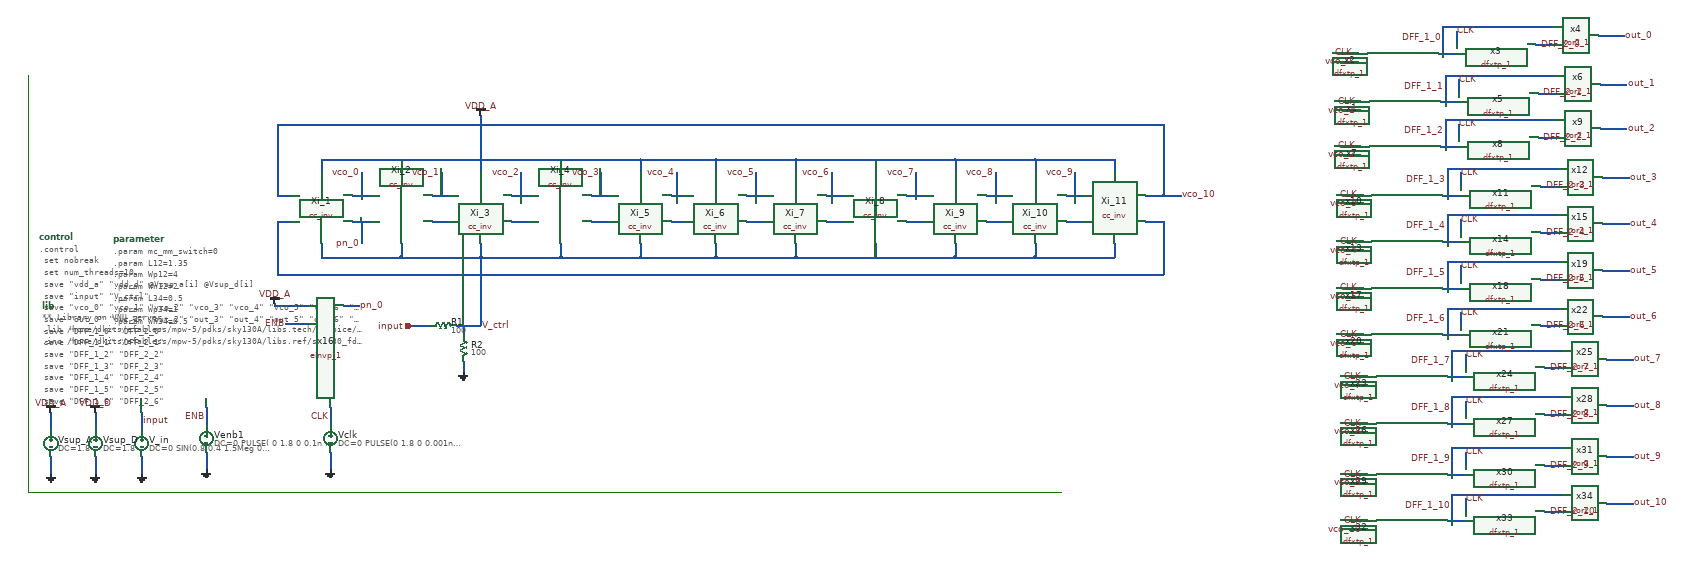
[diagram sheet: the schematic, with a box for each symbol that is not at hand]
v {xschem version=3.0.0 file_version=1.2 }
G {}
K {}
V {}
S {}
E {}
L 4 0 -540 -0 -0 {}
L 4 -0 0 520 -0 {}
L 4 520 -0 580 -0 {}
L 4 580 -0 800 0 {}
L 4 800 -0 885 0 {}
L 4 -0 -615 -0 -540 {}
L 4 885 -0 1180 -0 {}
L 4 1180 0 1210 0 {}
L 4 1210 -0 1310 -0 {}
L 4 -0 -860 0 -610 {}
L 4 0 -940 -0 -860 {}
L 4 1310 0 2330 -0 {}
N 50 -180 50 -140 { lab=VDD_A}
N 50 -80 50 -40 { lab=GND}
N 255 -80 255 -40 { lab=GND}
N 255 -180 255 -140 { lab=input}
N 400 -90 400 -50 { lab=GND}
N 400 -190 400 -150 { lab=ENB}
N 980 -375 980 -355 { lab=V_ctrl}
N 980 -295 980 -270 { lab=GND}
N 865 -375 905 -375 { lab=input}
N 150 -180 150 -140 { lab=VDD_D}
N 150 -80 150 -40 { lab=GND}
N 680 -90 680 -50 { lab=GND}
N 680 -190 680 -150 { lab=CLK}
N 3180 -990 3200 -990 { lab=DFF_1_0}
N 3400 -1010 3420 -1010 { lab=DFF_2_0}
N 3540 -1030 3600 -1030 { lab=out_0}
N 2960 -990 3000 -990 { lab=CLK}
N 2960 -970 3000 -970 { lab=vco_0}
N 3200 -1050 3420 -1050 { lab=DFF_1_0}
N 3200 -990 3220 -990 { lab=DFF_1_0}
N 3220 -1040 3220 -1010 { lab=CLK}
N 3190 -1050 3200 -1050 { lab=DFF_1_0}
N 3190 -1050 3190 -990 { lab=DFF_1_0}
N 3420 -1050 3440 -1050 { lab=DFF_1_0}
N 3420 -1010 3440 -1010 { lab=DFF_2_0}
N 3185 -880 3205 -880 { lab=DFF_1_1}
N 3405 -900 3425 -900 { lab=DFF_2_1}
N 3545 -920 3605 -920 { lab=out_1}
N 2965 -880 3005 -880 { lab=CLK}
N 2965 -860 3005 -860 { lab=vco_1}
N 3205 -940 3425 -940 { lab=DFF_1_1}
N 3205 -880 3225 -880 { lab=DFF_1_1}
N 3225 -930 3225 -900 { lab=CLK}
N 3195 -940 3205 -940 { lab=DFF_1_1}
N 3195 -940 3195 -880 { lab=DFF_1_1}
N 3425 -940 3445 -940 { lab=DFF_1_1}
N 3425 -900 3445 -900 { lab=DFF_2_1}
N 3185 -780 3205 -780 { lab=DFF_1_2}
N 3405 -800 3425 -800 { lab=DFF_2_2}
N 3545 -820 3605 -820 { lab=out_2}
N 2965 -780 3005 -780 { lab=CLK}
N 2965 -760 3005 -760 { lab=vco_2}
N 3205 -840 3425 -840 { lab=DFF_1_2}
N 3205 -780 3225 -780 { lab=DFF_1_2}
N 3225 -830 3225 -800 { lab=CLK}
N 3195 -840 3205 -840 { lab=DFF_1_2}
N 3195 -840 3195 -780 { lab=DFF_1_2}
N 3425 -840 3445 -840 { lab=DFF_1_2}
N 3425 -800 3445 -800 { lab=DFF_2_2}
N 3190 -670 3210 -670 { lab=DFF_1_3}
N 3410 -690 3430 -690 { lab=DFF_2_3}
N 3550 -710 3610 -710 { lab=out_3}
N 2970 -670 3010 -670 { lab=CLK}
N 2970 -650 3010 -650 { lab=vco_3}
N 3210 -730 3430 -730 { lab=DFF_1_3}
N 3210 -670 3230 -670 { lab=DFF_1_3}
N 3230 -720 3230 -690 { lab=CLK}
N 3200 -730 3210 -730 { lab=DFF_1_3}
N 3200 -730 3200 -670 { lab=DFF_1_3}
N 3430 -730 3450 -730 { lab=DFF_1_3}
N 3430 -690 3450 -690 { lab=DFF_2_3}
N 3190 -565 3210 -565 { lab=DFF_1_4}
N 3410 -585 3430 -585 { lab=DFF_2_4}
N 3550 -605 3610 -605 { lab=out_4}
N 2970 -565 3010 -565 { lab=CLK}
N 2970 -545 3010 -545 { lab=vco_4}
N 3210 -625 3430 -625 { lab=DFF_1_4}
N 3210 -565 3230 -565 { lab=DFF_1_4}
N 3230 -615 3230 -585 { lab=CLK}
N 3200 -625 3210 -625 { lab=DFF_1_4}
N 3200 -625 3200 -565 { lab=DFF_1_4}
N 3430 -625 3450 -625 { lab=DFF_1_4}
N 3430 -585 3450 -585 { lab=DFF_2_4}
N 730 -670 770 -670 { lab=vco_0}
N 910 -670 950 -670 { lab=vco_1}
N 1090 -670 1130 -670 { lab=vco_2}
N 1270 -670 1310 -670 { lab=vco_3}
N 1270 -610 1310 -610 { lab=#net1}
N 1090 -610 1130 -610 { lab=#net2}
N 910 -610 950 -610 { lab=#net3}
N 730 -610 770 -610 { lab=pn_0}
N 660 -560 660 -530 { lab=V_ctrl}
N 660 -530 840 -530 { lab=V_ctrl}
N 840 -560 840 -530 { lab=V_ctrl}
N 840 -530 1020 -530 { lab=V_ctrl}
N 1020 -560 1020 -530 { lab=V_ctrl}
N 1020 -530 1200 -530 { lab=V_ctrl}
N 1200 -560 1200 -530 { lab=V_ctrl}
N 1200 -530 1380 -530 { lab=V_ctrl}
N 1380 -560 1380 -530 { lab=V_ctrl}
N 660 -750 660 -720 { lab=VDD_A}
N 660 -750 1380 -750 { lab=VDD_A}
N 1380 -750 1380 -720 { lab=VDD_A}
N 1200 -750 1200 -720 { lab=VDD_A}
N 1020 -750 1020 -720 { lab=VDD_A}
N 840 -750 840 -720 { lab=VDD_A}
N 1450 -670 1480 -670 { lab=vco_4}
N 560 -490 1480 -490 { lab=#net4}
N 1450 -610 1480 -610 { lab=#net5}
N 1020 -530 1020 -450 { lab=V_ctrl}
N 1020 -850 1020 -750 { lab=VDD_A}
N 750 -720 750 -670 { lab=vco_0}
N 930 -720 930 -670 { lab=vco_1}
N 1110 -720 1110 -670 { lab=vco_2}
N 1290 -720 1290 -670 { lab=vco_3}
N 750 -610 750 -560 { lab=pn_0}
N 715 -420 745 -420 { lab=pn_0}
N 580 -420 630 -420 { lab=VDD_A}
N 580 -380 630 -380 { lab=ENB}
N 710 -420 715 -420 { lab=pn_0}
N 965 -375 1020 -375 { lab=V_ctrl}
N 1020 -400 1020 -375 { lab=V_ctrl}
N 1020 -450 1020 -400 { lab=V_ctrl}
N 555 -420 580 -420 { lab=VDD_A}
N 555 -425 555 -420 { lab=VDD_A}
N 560 -610 560 -490 { lab=#net4}
N 560 -610 590 -610 { lab=#net4}
N 560 -670 590 -670 { lab=vco_9}
N 560 -830 560 -670 { lab=vco_9}
N 560 -830 1480 -830 { lab=vco_9}
N 1380 -750 1550 -750 { lab=VDD_A}
N 1550 -750 1550 -720 { lab=VDD_A}
N 1550 -750 1730 -750 { lab=VDD_A}
N 1730 -750 1730 -720 { lab=VDD_A}
N 1380 -530 1550 -530 { lab=V_ctrl}
N 1550 -560 1550 -530 { lab=V_ctrl}
N 1550 -530 1730 -530 { lab=V_ctrl}
N 1730 -560 1730 -530 { lab=V_ctrl}
N 1620 -670 1660 -670 { lab=vco_5}
N 1620 -610 1660 -610 { lab=#net6}
N 1480 -830 1820 -830 { lab=vco_9}
N 1800 -670 1820 -670 { lab=vco_6}
N 1480 -490 1820 -490 { lab=#net4}
N 1800 -610 1820 -610 { lab=#net7}
N 1460 -720 1460 -670 { lab=vco_4}
N 1640 -720 1640 -670 { lab=vco_5}
N 3190 -460 3210 -460 { lab=DFF_1_5}
N 3410 -480 3430 -480 { lab=DFF_2_5}
N 3550 -500 3610 -500 { lab=out_5}
N 2970 -460 3010 -460 { lab=CLK}
N 2970 -440 3010 -440 { lab=vco_5}
N 3210 -520 3430 -520 { lab=DFF_1_5}
N 3210 -460 3230 -460 { lab=DFF_1_5}
N 3230 -510 3230 -480 { lab=CLK}
N 3200 -520 3210 -520 { lab=DFF_1_5}
N 3200 -520 3200 -460 { lab=DFF_1_5}
N 3430 -520 3450 -520 { lab=DFF_1_5}
N 3430 -480 3450 -480 { lab=DFF_2_5}
N 3190 -355 3210 -355 { lab=DFF_1_6}
N 3410 -375 3430 -375 { lab=DFF_2_6}
N 3550 -395 3610 -395 { lab=out_6}
N 2970 -355 3010 -355 { lab=CLK}
N 2970 -335 3010 -335 { lab=vco_6}
N 3210 -415 3430 -415 { lab=DFF_1_6}
N 3210 -355 3230 -355 { lab=DFF_1_6}
N 3230 -405 3230 -375 { lab=CLK}
N 3200 -415 3210 -415 { lab=DFF_1_6}
N 3200 -415 3200 -355 { lab=DFF_1_6}
N 3430 -415 3450 -415 { lab=DFF_1_6}
N 3430 -375 3450 -375 { lab=DFF_2_6}
N 1730 -750 1890 -750 { lab=VDD_A}
N 1890 -750 2070 -750 { lab=VDD_A}
N 1730 -530 1890 -530 { lab=V_ctrl}
N 1890 -530 2070 -530 { lab=V_ctrl}
N 1820 -830 2160 -830 { lab=vco_9}
N 1820 -490 2160 -490 { lab=#net4}
N 1820 -670 1840 -670 { lab=vco_6}
N 1820 -610 1840 -610 { lab=#net7}
N 1810 -720 1810 -670 { lab=vco_6}
N 1980 -670 2020 -670 { lab=vco_7}
N 1980 -610 2020 -610 { lab=#net8}
N 1910 -750 1910 -720 { lab=VDD_A}
N 2070 -750 2090 -750 { lab=VDD_A}
N 2090 -750 2090 -720 { lab=VDD_A}
N 1910 -560 1910 -530 { lab=V_ctrl}
N 2070 -530 2090 -530 { lab=V_ctrl}
N 2090 -560 2090 -530 { lab=V_ctrl}
N 2160 -830 2200 -830 { lab=vco_9}
N 2160 -670 2200 -670 { lab=vco_8}
N 2160 -490 2200 -490 { lab=#net4}
N 2160 -610 2200 -610 { lab=#net9}
N 2000 -720 2000 -670 { lab=vco_7}
N 3200 -260 3220 -260 { lab=DFF_1_7}
N 3420 -280 3440 -280 { lab=DFF_2_7}
N 3560 -300 3620 -300 { lab=out_7}
N 2980 -260 3020 -260 { lab=CLK}
N 2980 -240 3020 -240 { lab=vco_7}
N 3220 -320 3440 -320 { lab=DFF_1_7}
N 3220 -260 3240 -260 { lab=DFF_1_7}
N 3240 -310 3240 -280 { lab=CLK}
N 3210 -320 3220 -320 { lab=DFF_1_7}
N 3210 -320 3210 -260 { lab=DFF_1_7}
N 3440 -320 3460 -320 { lab=DFF_1_7}
N 3440 -280 3460 -280 { lab=DFF_2_7}
N 3200 -155 3220 -155 { lab=DFF_1_8}
N 3420 -175 3440 -175 { lab=DFF_2_8}
N 3560 -195 3620 -195 { lab=out_8}
N 2980 -155 3020 -155 { lab=CLK}
N 2980 -135 3020 -135 { lab=vco_8}
N 3220 -215 3440 -215 { lab=DFF_1_8}
N 3220 -155 3240 -155 { lab=DFF_1_8}
N 3240 -205 3240 -175 { lab=CLK}
N 3210 -215 3220 -215 { lab=DFF_1_8}
N 3210 -215 3210 -155 { lab=DFF_1_8}
N 3440 -215 3460 -215 { lab=DFF_1_8}
N 3440 -175 3460 -175 { lab=DFF_2_8}
N 2090 -750 2270 -750 { lab=VDD_A}
N 2270 -750 2270 -720 { lab=VDD_A}
N 2270 -750 2450 -750 { lab=VDD_A}
N 2450 -750 2450 -720 { lab=VDD_A}
N 2090 -530 2270 -530 { lab=V_ctrl}
N 2270 -560 2270 -530 { lab=V_ctrl}
N 2270 -530 2450 -530 { lab=V_ctrl}
N 2450 -560 2450 -530 { lab=V_ctrl}
N 2200 -490 2560 -490 { lab=#net4}
N 2560 -610 2560 -490 { lab=#net4}
N 2520 -610 2560 -610 { lab=#net4}
N 2200 -830 2560 -830 { lab=vco_9}
N 2560 -830 2560 -670 { lab=vco_9}
N 2520 -670 2560 -670 { lab=vco_9}
N 2180 -720 2180 -670 { lab=vco_8}
N 2340 -670 2380 -670 { lab=vco_9}
N 2340 -610 2380 -610 { lab=#net10}
N 2560 -670 2600 -670 { lab=vco_9}
N 2360 -720 2360 -670 { lab=vco_9}
N 3200 -40 3220 -40 { lab=DFF_1_7}
N 3420 -60 3440 -60 { lab=DFF_2_7}
N 3560 -80 3620 -80 { lab=out_7}
N 2980 -40 3020 -40 { lab=CLK}
N 2980 -20 3020 -20 { lab=vco_7}
N 3220 -100 3440 -100 { lab=DFF_1_7}
N 3220 -40 3240 -40 { lab=DFF_1_7}
N 3240 -90 3240 -60 { lab=CLK}
N 3210 -100 3220 -100 { lab=DFF_1_7}
N 3210 -100 3210 -40 { lab=DFF_1_7}
N 3440 -100 3460 -100 { lab=DFF_1_7}
N 3440 -60 3460 -60 { lab=DFF_2_7}
N 3200 65 3220 65 { lab=DFF_1_8}
N 3420 45 3440 45 { lab=DFF_2_8}
N 3560 25 3620 25 { lab=out_8}
N 2980 65 3020 65 { lab=CLK}
N 2980 85 3020 85 { lab=vco_8}
N 3220 5 3440 5 { lab=DFF_1_8}
N 3220 65 3240 65 { lab=DFF_1_8}
N 3240 15 3240 45 { lab=CLK}
N 3210 5 3220 5 { lab=DFF_1_8}
N 3210 5 3210 65 { lab=DFF_1_8}
N 3440 5 3460 5 { lab=DFF_1_8}
N 3440 45 3460 45 { lab=DFF_2_8}
C {devices/vsource.sym} 50 -110 0 0 {name=Vsup_A value="DC=1.8"}
C {devices/vsource.sym} 255 -110 0 0 {name=V_in value="DC=0 SIN(0.8 0.4 1.5Meg 0 0 0)"}
C {devices/vsource.sym} 400 -120 0 0 {name=Venb1 value="DC=0 PULSE( 0 1.8 0 0.1n 0.1n 20n 1)"}
C {devices/vdd.sym} 50 -180 0 0 {name=l13 lab=VDD_A}
C {devices/gnd.sym} 50 -40 0 0 {name=l14 lab=GND}
C {devices/gnd.sym} 255 -40 0 0 {name=l15 lab=GND}
C {devices/gnd.sym} 400 -50 0 0 {name=l17 lab=GND}
C {devices/lab_pin.sym} 255 -160 2 0 {name=l18 sig_type=std_logic lab=input}
C {devices/lab_pin.sym} 400 -170 0 0 {name=l19 sig_type=std_logic lab=ENB}
C {devices/code.sym} 25 -575 0 0 {name=control only_toplevel=false value="
.control
    set nobreak
    set num_threads=10
    
    save \\"vdd_a\\" \\"vdd_d\\" @Vsup_a[i] @Vsup_d[i]
    save \\"input\\" \\"V_ctrl\\"
    save \\"vco_0\\" \\"vco_1\\" \\"vco_2\\" \\"vco_3\\" \\"vco_4\\" \\"vco_5\\" \\"vco_6\\" \\"vco_7\\" \\"vco_8\\" \\"vco_9\\" \\"vco_10\\"
    save \\"out_0\\" \\"out_1\\" \\"out_2\\" \\"out_3\\" \\"out_4\\" \\"out_5\\" \\"out_6\\" \\"out_7\\" \\"out_8\\" \\"out_9\\" \\"out_10\\"
    save \\"DFF_1_0\\" \\"DFF_2_0\\"
    save \\"DFF_1_1\\" \\"DFF_2_1\\"
    save \\"DFF_1_2\\" \\"DFF_2_2\\"
    save \\"DFF_1_3\\" \\"DFF_2_3\\"
    save \\"DFF_1_4\\" \\"DFF_2_4\\"
    save \\"DFF_1_5\\" \\"DFF_2_5\\"
    save \\"DFF_1_6\\" \\"DFF_2_6\\"
    save \\"DFF_1_7\\" \\"DFF_2_7\\"
    save \\"DFF_1_8\\" \\"DFF_2_8\\"
    save \\"DFF_1_9\\" \\"DFF_2_9\\"
    save \\"DFF_1_10\\" \\"DFF_2_10\\"
    save \\"CLK\\"
    TRAN 10n 5u

*Calculate Power of system
    MEAS TRAN I_vco AVG @Vsup_a[i] FROM=1u TO=5u
    MEAS TRAN V_vco AVG vdd_a FROM=1u TO=5u
    MEAS TRAN I_qz AVG @Vsup_d[i] FROM=1u TO=5u
    MEAS TRAN V_qz AVG vdd_d FROM=1u TO=5u
    let Power_vco=I_vco*V_vco
    let Power_qz=I_qz*V_qz
    let Power=Power_vco+Power_qz
    echo \\"The power of system is: \\"
    print Power

*Calculate Frequency of VCO
    MEAS TRAN prd TRIG vco_0 VAL=0.8 RISE=10 TARG vco_0 VAL=0.8 RISE=20
    let frequency=10/prd
    echo \\"The AVG frequency of VCO is: \\"
    print frequency
    plot vco_0+2 CLK+2 DFF_1_0 DFF_2_0 out_0-2

    print vco_0 vco_1 vco_2 > show_all_11/data_vco_0.txt
    print vco_3 vco_4 vco_5 > show_all_11/data_vco_1.txt
    print vco_6 vco_7 vco_8 > show_all_11/data_vco_2.txt
    print vco_9 vco_10 > show_all_11/data_vco_3.txt

    print clk out_0 out_1 > show_all_11/data_out_0.txt
    print out_2 out_3 out_4 > show_all_11/data_out_1.txt
    print out_5 out_6 out_7 > show_all_11/data_out_2.txt
    print out_8 out_9 out_10 > show_all_11/data_out_3.txt

*    plot input V_ctrl V_ctrl-2 vco_0-2 V_ctrl-4 out_0-4
.endc
"}
C {devices/code.sym} 30 -420 0 0 {name=lib only_toplevel=false value="
** Library on VNU server
.lib /home/dkits/efabless/mpw-5/pdks/sky130A/libs.tech/ngspice/sky130.lib.spice tt
.inc /home/dkits/efabless/mpw-5/pdks/sky130A/libs.ref/sky130_fd_sc_hd/spice/sky130_fd_sc_hd.spice
"}
C {devices/code_shown.sym} 190 -570 0 0 {name=parameter only_toplevel=false value="
.param mc_mm_switch=0
.param L12=1.35
.param Wp12=4
.param Wn12=2
.param L34=0.5
.param Wp34=1
.param Wn34=0.5
"}
C {devices/res.sym} 935 -375 3 0 {name=R1
value=100
footprint=1206
device=resistor
m=1}
C {devices/res.sym} 980 -325 0 0 {name=R2
value=100
footprint=1206
device=resistor
m=1}
C {devices/gnd.sym} 980 -270 0 0 {name=l7 lab=GND}
C {devices/ipin.sym} 865 -375 0 0 {name=p1 lab=input}
C {devices/vsource.sym} 150 -110 0 0 {name=Vsup_D value="DC=1.8"}
C {devices/vdd.sym} 150 -180 0 0 {name=l8 lab=VDD_D}
C {devices/gnd.sym} 150 -40 0 0 {name=l9 lab=GND}
C {devices/vsource.sym} 680 -120 0 0 {name=Vclk value="DC=0 PULSE(0 1.8 0 0.001n 0.001n 2.499n 5n 0)"
*PULSE(0 1.8 0 0.001n 0.001n 6.2n 12.5n 0)" 80MHz}
C {devices/gnd.sym} 680 -50 0 0 {name=l10 lab=GND}
C {devices/lab_pin.sym} 680 -170 0 0 {name=l16 sig_type=std_logic lab=CLK}
C {devices/lab_pin.sym} 3600 -1030 2 0 {name=l23 sig_type=std_logic lab=out_0}
C {sky130_stdcells/dfxtp_1.sym} 3090 -980 0 0 {name=x2 VGND=GND VNB=GND VPB=VDD_D VPWR=VDD_D prefix=sky130_fd_sc_hd__ }
C {sky130_stdcells/dfxtp_1.sym} 3310 -1000 0 0 {name=x3 VGND=GND VNB=GND VPB=VDD_D VPWR=VDD_D prefix=sky130_fd_sc_hd__ }
C {sky130_stdcells/xor2_1.sym} 3500 -1030 0 0 {name=x4 VGND=GND VNB=GND VPB=VDD_D VPWR=VDD_D prefix=sky130_fd_sc_hd__ }
C {devices/lab_wire.sym} 2990 -990 0 0 {name=l28 sig_type=std_logic lab=CLK}
C {devices/lab_wire.sym} 3220 -1040 2 0 {name=l29 sig_type=std_logic lab=CLK}
C {devices/lab_wire.sym} 3190 -1025 0 0 {name=l30 sig_type=std_logic lab=DFF_1_0}
C {devices/lab_wire.sym} 3410 -1010 2 0 {name=l31 sig_type=std_logic lab=DFF_2_0}
C {devices/lab_wire.sym} 2990 -970 0 0 {name=l20 sig_type=std_logic lab=vco_0}
C {devices/lab_pin.sym} 3605 -920 2 0 {name=l21 sig_type=std_logic lab=out_1}
C {sky130_stdcells/dfxtp_1.sym} 3095 -870 0 0 {name=x1 VGND=GND VNB=GND VPB=VDD_D VPWR=VDD_D prefix=sky130_fd_sc_hd__ }
C {sky130_stdcells/dfxtp_1.sym} 3315 -890 0 0 {name=x5 VGND=GND VNB=GND VPB=VDD_D VPWR=VDD_D prefix=sky130_fd_sc_hd__ }
C {sky130_stdcells/xor2_1.sym} 3505 -920 0 0 {name=x6 VGND=GND VNB=GND VPB=VDD_D VPWR=VDD_D prefix=sky130_fd_sc_hd__ }
C {devices/lab_wire.sym} 2995 -880 0 0 {name=l22 sig_type=std_logic lab=CLK}
C {devices/lab_wire.sym} 3225 -930 2 0 {name=l24 sig_type=std_logic lab=CLK}
C {devices/lab_wire.sym} 3195 -915 0 0 {name=l25 sig_type=std_logic lab=DFF_1_1}
C {devices/lab_wire.sym} 3415 -900 2 0 {name=l26 sig_type=std_logic lab=DFF_2_1}
C {devices/lab_wire.sym} 2995 -860 0 0 {name=l27 sig_type=std_logic lab=vco_1}
C {devices/lab_pin.sym} 3605 -820 2 0 {name=l32 sig_type=std_logic lab=out_2}
C {sky130_stdcells/dfxtp_1.sym} 3095 -770 0 0 {name=x7 VGND=GND VNB=GND VPB=VDD_D VPWR=VDD_D prefix=sky130_fd_sc_hd__ }
C {sky130_stdcells/dfxtp_1.sym} 3315 -790 0 0 {name=x8 VGND=GND VNB=GND VPB=VDD_D VPWR=VDD_D prefix=sky130_fd_sc_hd__ }
C {sky130_stdcells/xor2_1.sym} 3505 -820 0 0 {name=x9 VGND=GND VNB=GND VPB=VDD_D VPWR=VDD_D prefix=sky130_fd_sc_hd__ }
C {devices/lab_wire.sym} 2995 -780 0 0 {name=l33 sig_type=std_logic lab=CLK}
C {devices/lab_wire.sym} 3225 -830 2 0 {name=l34 sig_type=std_logic lab=CLK}
C {devices/lab_wire.sym} 3195 -815 0 0 {name=l35 sig_type=std_logic lab=DFF_1_2}
C {devices/lab_wire.sym} 3415 -800 2 0 {name=l36 sig_type=std_logic lab=DFF_2_2}
C {devices/lab_wire.sym} 2995 -760 0 0 {name=l37 sig_type=std_logic lab=vco_2}
C {devices/lab_pin.sym} 3610 -710 2 0 {name=l38 sig_type=std_logic lab=out_3}
C {sky130_stdcells/dfxtp_1.sym} 3100 -660 0 0 {name=x10 VGND=GND VNB=GND VPB=VDD_D VPWR=VDD_D prefix=sky130_fd_sc_hd__ }
C {sky130_stdcells/dfxtp_1.sym} 3320 -680 0 0 {name=x11 VGND=GND VNB=GND VPB=VDD_D VPWR=VDD_D prefix=sky130_fd_sc_hd__ }
C {sky130_stdcells/xor2_1.sym} 3510 -710 0 0 {name=x12 VGND=GND VNB=GND VPB=VDD_D VPWR=VDD_D prefix=sky130_fd_sc_hd__ }
C {devices/lab_wire.sym} 3000 -670 0 0 {name=l39 sig_type=std_logic lab=CLK}
C {devices/lab_wire.sym} 3230 -720 2 0 {name=l40 sig_type=std_logic lab=CLK}
C {devices/lab_wire.sym} 3200 -705 0 0 {name=l41 sig_type=std_logic lab=DFF_1_3}
C {devices/lab_wire.sym} 3420 -690 2 0 {name=l42 sig_type=std_logic lab=DFF_2_3}
C {devices/lab_wire.sym} 3000 -650 0 0 {name=l43 sig_type=std_logic lab=vco_3}
C {devices/lab_pin.sym} 3610 -605 2 0 {name=l44 sig_type=std_logic lab=out_4}
C {sky130_stdcells/dfxtp_1.sym} 3100 -555 0 0 {name=x13 VGND=GND VNB=GND VPB=VDD_D VPWR=VDD_D prefix=sky130_fd_sc_hd__ }
C {sky130_stdcells/dfxtp_1.sym} 3320 -575 0 0 {name=x14 VGND=GND VNB=GND VPB=VDD_D VPWR=VDD_D prefix=sky130_fd_sc_hd__ }
C {sky130_stdcells/xor2_1.sym} 3510 -605 0 0 {name=x15 VGND=GND VNB=GND VPB=VDD_D VPWR=VDD_D prefix=sky130_fd_sc_hd__ }
C {devices/lab_wire.sym} 3000 -565 0 0 {name=l45 sig_type=std_logic lab=CLK}
C {devices/lab_wire.sym} 3230 -615 2 0 {name=l46 sig_type=std_logic lab=CLK}
C {devices/lab_wire.sym} 3200 -600 0 0 {name=l47 sig_type=std_logic lab=DFF_1_4}
C {devices/lab_wire.sym} 3420 -585 2 0 {name=l48 sig_type=std_logic lab=DFF_2_4}
C {devices/lab_wire.sym} 3000 -545 0 0 {name=l49 sig_type=std_logic lab=vco_4}
C {/home/userdata/k63D/toind_63d/Desktop/project/circuit_model/lib/cc_inv.sym} 660 -640 0 0 {name=Xi_1 L12=\\"L12\\" Wp12=\\"Wp12\\" Wn12=\\"Wn12\\"
 L34=\\"L34\\" Wp34=\\"Wp34\\" Wn34=\\"Wn34\\"}
C {/home/userdata/k63D/toind_63d/Desktop/project/circuit_model/lib/cc_inv.sym} 840 -640 0 0 {name=Xi_2 L12=\\"L12\\" Wp12=\\"Wp12\\" Wn12=\\"Wn12\\"
 L34=\\"L34\\" Wp34=\\"Wp34\\" Wn34=\\"Wn34\\"}
C {/home/userdata/k63D/toind_63d/Desktop/project/circuit_model/lib/cc_inv.sym} 1020 -640 0 0 {name=Xi_3 L12=\\"L12\\" Wp12=\\"Wp12\\" Wn12=\\"Wn12\\"
 L34=\\"L34\\" Wp34=\\"Wp34\\" Wn34=\\"Wn34\\"}
C {/home/userdata/k63D/toind_63d/Desktop/project/circuit_model/lib/cc_inv.sym} 1200 -640 0 0 {name=Xi_4 L12=\\"L12\\" Wp12=\\"Wp12\\" Wn12=\\"Wn12\\"
 L34=\\"L34\\" Wp34=\\"Wp34\\" Wn34=\\"Wn34\\"}
C {/home/userdata/k63D/toind_63d/Desktop/project/circuit_model/lib/cc_inv.sym} 1380 -640 0 0 {name=Xi_5 L12=\\"L12\\" Wp12=\\"Wp12\\" Wn12=\\"Wn12\\"
 L34=\\"L34\\" Wp34=\\"Wp34\\" Wn34=\\"Wn34\\"}
C {devices/vdd.sym} 1020 -850 0 0 {name=l51 lab=VDD_A}
C {sky130_stdcells/einvp_1.sym} 670 -420 0 0 {name=x16 VGND=GND VNB=GND VPB=VDD_A VPWR=VDD_A prefix=sky130_fd_sc_hd__ }
C {devices/lab_pin.sym} 580 -380 0 0 {name=l52 sig_type=std_logic lab=ENB}
C {devices/lab_pin.sym} 745 -420 2 0 {name=l54 sig_type=std_logic lab=pn_0}
C {devices/lab_pin.sym} 750 -560 0 0 {name=l55 sig_type=std_logic lab=pn_0}
C {devices/lab_wire.sym} 750 -720 0 0 {name=l56 sig_type=std_logic lab=vco_0}
C {devices/lab_wire.sym} 930 -720 0 0 {name=l57 sig_type=std_logic lab=vco_1}
C {devices/lab_wire.sym} 1110 -720 0 0 {name=l58 sig_type=std_logic lab=vco_2}
C {devices/lab_wire.sym} 1290 -720 0 0 {name=l59 sig_type=std_logic lab=vco_3}
C {devices/lab_wire.sym} 1460 -720 0 0 {name=l60 sig_type=std_logic lab=vco_4}
C {devices/lab_wire.sym} 1020 -375 2 0 {name=l61 sig_type=std_logic lab=V_ctrl}
C {devices/vdd.sym} 555 -425 0 0 {name=l1 lab=VDD_A}
C {/home/userdata/k63D/toind_63d/Desktop/project/circuit_model/lib/cc_inv.sym} 1550 -640 0 0 {name=Xi_6 L12=\\"L12\\" Wp12=\\"Wp12\\" Wn12=\\"Wn12\\"
 L34=\\"L34\\" Wp34=\\"Wp34\\" Wn34=\\"Wn34\\"}
C {/home/userdata/k63D/toind_63d/Desktop/project/circuit_model/lib/cc_inv.sym} 1730 -640 0 0 {name=Xi_7 L12=\\"L12\\" Wp12=\\"Wp12\\" Wn12=\\"Wn12\\"
 L34=\\"L34\\" Wp34=\\"Wp34\\" Wn34=\\"Wn34\\"}
C {devices/lab_wire.sym} 1640 -720 0 0 {name=l2 sig_type=std_logic lab=vco_5}
C {devices/lab_wire.sym} 1810 -720 0 0 {name=l3 sig_type=std_logic lab=vco_6}
C {devices/lab_pin.sym} 3610 -500 2 0 {name=l4 sig_type=std_logic lab=out_5}
C {sky130_stdcells/dfxtp_1.sym} 3100 -450 0 0 {name=x17 VGND=GND VNB=GND VPB=VDD_D VPWR=VDD_D prefix=sky130_fd_sc_hd__ }
C {sky130_stdcells/dfxtp_1.sym} 3320 -470 0 0 {name=x18 VGND=GND VNB=GND VPB=VDD_D VPWR=VDD_D prefix=sky130_fd_sc_hd__ }
C {sky130_stdcells/xor2_1.sym} 3510 -500 0 0 {name=x19 VGND=GND VNB=GND VPB=VDD_D VPWR=VDD_D prefix=sky130_fd_sc_hd__ }
C {devices/lab_wire.sym} 3000 -460 0 0 {name=l5 sig_type=std_logic lab=CLK}
C {devices/lab_wire.sym} 3230 -510 2 0 {name=l6 sig_type=std_logic lab=CLK}
C {devices/lab_wire.sym} 3200 -495 0 0 {name=l11 sig_type=std_logic lab=DFF_1_5}
C {devices/lab_wire.sym} 3420 -480 2 0 {name=l12 sig_type=std_logic lab=DFF_2_5}
C {devices/lab_wire.sym} 3000 -440 0 0 {name=l50 sig_type=std_logic lab=vco_5}
C {devices/lab_pin.sym} 3610 -395 2 0 {name=l53 sig_type=std_logic lab=out_6}
C {sky130_stdcells/dfxtp_1.sym} 3100 -345 0 0 {name=x20 VGND=GND VNB=GND VPB=VDD_D VPWR=VDD_D prefix=sky130_fd_sc_hd__ }
C {sky130_stdcells/dfxtp_1.sym} 3320 -365 0 0 {name=x21 VGND=GND VNB=GND VPB=VDD_D VPWR=VDD_D prefix=sky130_fd_sc_hd__ }
C {sky130_stdcells/xor2_1.sym} 3510 -395 0 0 {name=x22 VGND=GND VNB=GND VPB=VDD_D VPWR=VDD_D prefix=sky130_fd_sc_hd__ }
C {devices/lab_wire.sym} 3000 -355 0 0 {name=l62 sig_type=std_logic lab=CLK}
C {devices/lab_wire.sym} 3230 -405 2 0 {name=l63 sig_type=std_logic lab=CLK}
C {devices/lab_wire.sym} 3200 -390 0 0 {name=l64 sig_type=std_logic lab=DFF_1_6}
C {devices/lab_wire.sym} 3420 -375 2 0 {name=l65 sig_type=std_logic lab=DFF_2_6}
C {devices/lab_wire.sym} 3000 -335 0 0 {name=l66 sig_type=std_logic lab=vco_6}
C {/home/userdata/k63D/toind_63d/Desktop/project/circuit_model/lib/cc_inv.sym} 1910 -640 0 0 {name=Xi_8 L12=\\"L12\\" Wp12=\\"Wp12\\" Wn12=\\"Wn12\\"
 L34=\\"L34\\" Wp34=\\"Wp34\\" Wn34=\\"Wn34\\"}
C {/home/userdata/k63D/toind_63d/Desktop/project/circuit_model/lib/cc_inv.sym} 2090 -640 0 0 {name=Xi_9 L12=\\"L12\\" Wp12=\\"Wp12\\" Wn12=\\"Wn12\\"
 L34=\\"L34\\" Wp34=\\"Wp34\\" Wn34=\\"Wn34\\"}
C {devices/lab_wire.sym} 2000 -720 0 0 {name=l67 sig_type=std_logic lab=vco_7}
C {devices/lab_wire.sym} 2180 -720 0 0 {name=l68 sig_type=std_logic lab=vco_8}
C {devices/lab_pin.sym} 3620 -300 2 0 {name=l69 sig_type=std_logic lab=out_7}
C {sky130_stdcells/dfxtp_1.sym} 3110 -250 0 0 {name=x23 VGND=GND VNB=GND VPB=VDD_D VPWR=VDD_D prefix=sky130_fd_sc_hd__ }
C {sky130_stdcells/dfxtp_1.sym} 3330 -270 0 0 {name=x24 VGND=GND VNB=GND VPB=VDD_D VPWR=VDD_D prefix=sky130_fd_sc_hd__ }
C {sky130_stdcells/xor2_1.sym} 3520 -300 0 0 {name=x25 VGND=GND VNB=GND VPB=VDD_D VPWR=VDD_D prefix=sky130_fd_sc_hd__ }
C {devices/lab_wire.sym} 3010 -260 0 0 {name=l70 sig_type=std_logic lab=CLK}
C {devices/lab_wire.sym} 3240 -310 2 0 {name=l71 sig_type=std_logic lab=CLK}
C {devices/lab_wire.sym} 3210 -295 0 0 {name=l72 sig_type=std_logic lab=DFF_1_7}
C {devices/lab_wire.sym} 3430 -280 2 0 {name=l73 sig_type=std_logic lab=DFF_2_7}
C {devices/lab_wire.sym} 3010 -240 0 0 {name=l74 sig_type=std_logic lab=vco_7}
C {devices/lab_pin.sym} 3620 -195 2 0 {name=l75 sig_type=std_logic lab=out_8}
C {sky130_stdcells/dfxtp_1.sym} 3110 -145 0 0 {name=x26 VGND=GND VNB=GND VPB=VDD_D VPWR=VDD_D prefix=sky130_fd_sc_hd__ }
C {sky130_stdcells/dfxtp_1.sym} 3330 -165 0 0 {name=x27 VGND=GND VNB=GND VPB=VDD_D VPWR=VDD_D prefix=sky130_fd_sc_hd__ }
C {sky130_stdcells/xor2_1.sym} 3520 -195 0 0 {name=x28 VGND=GND VNB=GND VPB=VDD_D VPWR=VDD_D prefix=sky130_fd_sc_hd__ }
C {devices/lab_wire.sym} 3010 -155 0 0 {name=l76 sig_type=std_logic lab=CLK}
C {devices/lab_wire.sym} 3240 -205 2 0 {name=l77 sig_type=std_logic lab=CLK}
C {devices/lab_wire.sym} 3210 -190 0 0 {name=l78 sig_type=std_logic lab=DFF_1_8}
C {devices/lab_wire.sym} 3430 -175 2 0 {name=l79 sig_type=std_logic lab=DFF_2_8}
C {devices/lab_wire.sym} 3010 -135 0 0 {name=l80 sig_type=std_logic lab=vco_8}
C {/home/userdata/k63D/toind_63d/Desktop/project/circuit_model/lib/cc_inv.sym} 2270 -640 0 0 {name=Xi_10 L12=\\"L12\\" Wp12=\\"Wp12\\" Wn12=\\"Wn12\\"
 L34=\\"L34\\" Wp34=\\"Wp34\\" Wn34=\\"Wn34\\"}
C {/home/userdata/k63D/toind_63d/Desktop/project/circuit_model/lib/cc_inv.sym} 2450 -640 0 0 {name=Xi_11 L12=\\"L12\\" Wp12=\\"Wp12\\" Wn12=\\"Wn12\\"
 L34=\\"L34\\" Wp34=\\"Wp34\\" Wn34=\\"Wn34\\"}
C {devices/lab_wire.sym} 2360 -720 0 0 {name=l81 sig_type=std_logic lab=vco_9}
C {devices/lab_wire.sym} 2600 -670 2 0 {name=l82 sig_type=std_logic lab=vco_10}
C {devices/lab_pin.sym} 3620 -80 2 0 {name=l83 sig_type=std_logic lab=out_9}
C {sky130_stdcells/dfxtp_1.sym} 3110 -30 0 0 {name=x29 VGND=GND VNB=GND VPB=VDD_D VPWR=VDD_D prefix=sky130_fd_sc_hd__ }
C {sky130_stdcells/dfxtp_1.sym} 3330 -50 0 0 {name=x30 VGND=GND VNB=GND VPB=VDD_D VPWR=VDD_D prefix=sky130_fd_sc_hd__ }
C {sky130_stdcells/xor2_1.sym} 3520 -80 0 0 {name=x31 VGND=GND VNB=GND VPB=VDD_D VPWR=VDD_D prefix=sky130_fd_sc_hd__ }
C {devices/lab_wire.sym} 3010 -40 0 0 {name=l84 sig_type=std_logic lab=CLK}
C {devices/lab_wire.sym} 3240 -90 2 0 {name=l85 sig_type=std_logic lab=CLK}
C {devices/lab_wire.sym} 3210 -75 0 0 {name=l86 sig_type=std_logic lab=DFF_1_9}
C {devices/lab_wire.sym} 3430 -60 2 0 {name=l87 sig_type=std_logic lab=DFF_2_9}
C {devices/lab_wire.sym} 3010 -20 0 0 {name=l88 sig_type=std_logic lab=vco_9}
C {devices/lab_pin.sym} 3620 25 2 0 {name=l89 sig_type=std_logic lab=out_10}
C {sky130_stdcells/dfxtp_1.sym} 3110 75 0 0 {name=x32 VGND=GND VNB=GND VPB=VDD_D VPWR=VDD_D prefix=sky130_fd_sc_hd__ }
C {sky130_stdcells/dfxtp_1.sym} 3330 55 0 0 {name=x33 VGND=GND VNB=GND VPB=VDD_D VPWR=VDD_D prefix=sky130_fd_sc_hd__ }
C {sky130_stdcells/xor2_1.sym} 3520 25 0 0 {name=x34 VGND=GND VNB=GND VPB=VDD_D VPWR=VDD_D prefix=sky130_fd_sc_hd__ }
C {devices/lab_wire.sym} 3010 65 0 0 {name=l90 sig_type=std_logic lab=CLK}
C {devices/lab_wire.sym} 3240 15 2 0 {name=l91 sig_type=std_logic lab=CLK}
C {devices/lab_wire.sym} 3210 30 0 0 {name=l92 sig_type=std_logic lab=DFF_1_10}
C {devices/lab_wire.sym} 3430 45 2 0 {name=l93 sig_type=std_logic lab=DFF_2_10}
C {devices/lab_wire.sym} 3010 85 0 0 {name=l94 sig_type=std_logic lab=vco_10}
